VERSION 5.7 ;
  NOWIREEXTENSIONATPIN ON ;
  DIVIDERCHAR "/" ;
  BUSBITCHARS "[]" ;
SITE unit
  SYMMETRY Y ;
  CLASS CORE ;
  SIZE 0.010 BY 0.010 ;
END unit

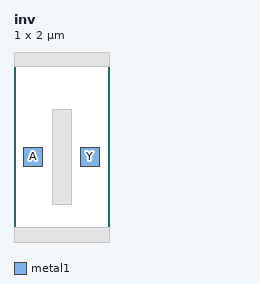
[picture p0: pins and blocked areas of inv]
MACRO inv
  CLASS BLOCK ;
  FOREIGN inv ;
  ORIGIN 0.000 0.000 ;
  SIZE 1.000 BY 2.000 ;
  SITE unit ;
  PIN A
    DIRECTION INPUT ;
    USE SIGNAL ;
    PORT
      LAYER metal1 ;
        RECT 0.100 0.800 0.300 1.000 ;
    END
  END A
  PIN Y
    DIRECTION OUTPUT ;
    USE SIGNAL ;
    PORT
      LAYER metal1 ;
        RECT 0.700 0.800 0.900 1.000 ;
    END
  END Y
  OBS
      LAYER metal1 ;
        RECT 0.000 1.850 1.000 2.000 ;
        RECT 0.400 0.400 0.600 1.400 ;
        RECT 0.000 0.000 1.000 0.150 ;
  END
END inv
END LIBRARY

